VERSION 5.7 ;
  NOWIREEXTENSIONATPIN ON ;
  DIVIDERCHAR "/" ;
  BUSBITCHARS "[]" ;
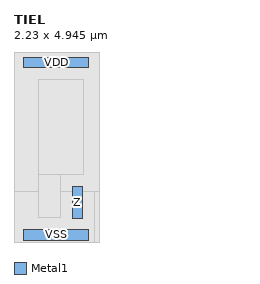
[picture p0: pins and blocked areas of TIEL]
MACRO TIEL
  CLASS core ;
  FOREIGN TIEL ;
  ORIGIN 0.255 0.190 ;
  SIZE 2.230 BY 4.945 ;
  SITE site056um ;
  PIN VSS
    DIRECTION INOUT ;
    USE GROUND ;
    PORT
      LAYER Metal1 ;
        RECT 0.000 -0.140 1.680 0.140 ;
    END
  END VSS
  PIN VDD
    DIRECTION INOUT ;
    USE POWER ;
    PORT
      LAYER Metal1 ;
        RECT 0.000 4.340 1.680 4.620 ;
    END
  END VDD
  PIN Z
    DIRECTION OUTPUT ;
    USE SIGNAL ;
    ANTENNADIFFAREA 0.151600 ;
    PORT
      LAYER Metal1 ;
        RECT 1.260 0.420 1.540 1.260 ;
    END
  END Z
  OBS
      LAYER Nwell ;
        RECT -0.255 1.135 1.975 4.755 ;
      LAYER Pwell ;
        RECT -0.255 -0.190 1.830 1.135 ;
      LAYER Nwell ;
        RECT 1.830 -0.190 1.975 1.135 ;
      LAYER Metal1 ;
        RECT 0.370 1.560 1.550 4.040 ;
        RECT 0.370 0.440 0.960 1.560 ;
  END
END TIEL
END LIBRARY

